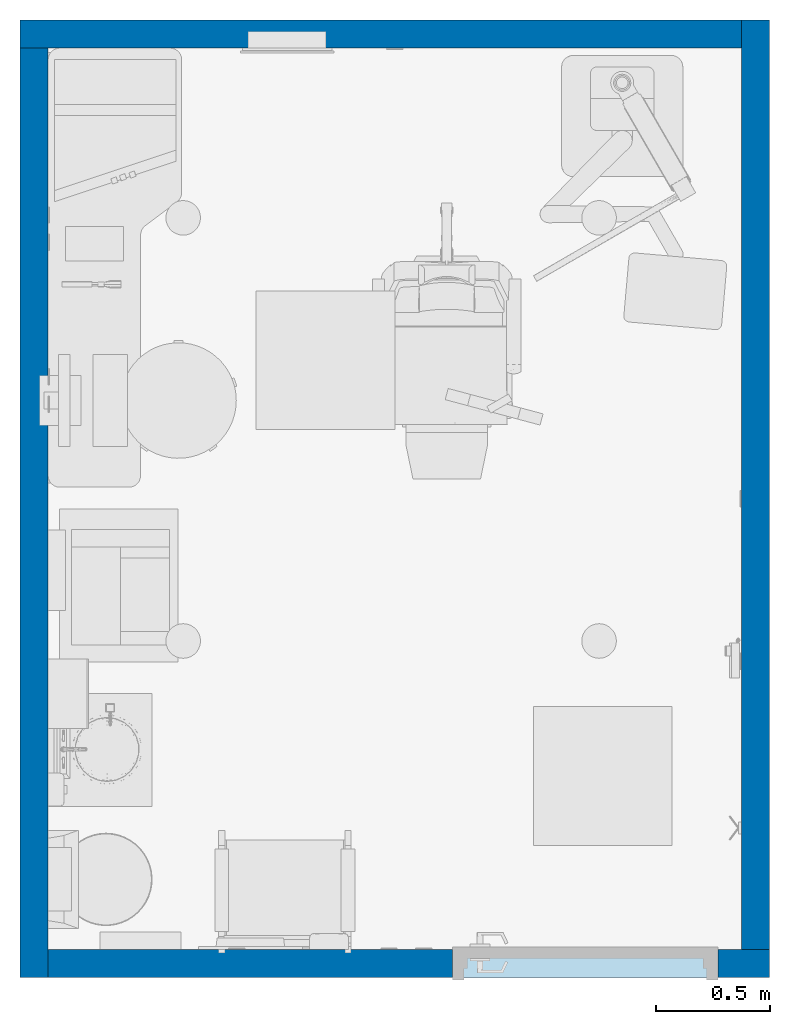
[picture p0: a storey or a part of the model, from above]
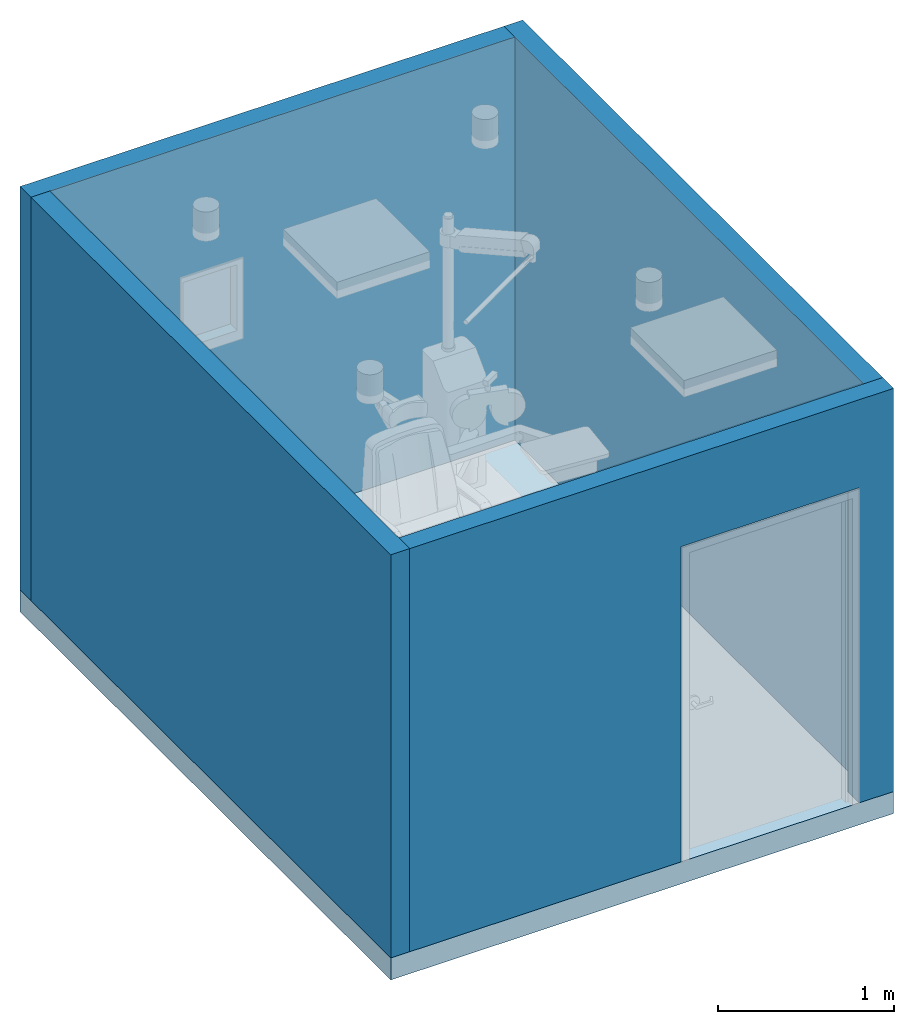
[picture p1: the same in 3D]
Properties of the parts of a building model (IFC2X3)

# File
Description: ViewDefinition [CoordinationView_V2.0]
File name: (ROOM CODE)
Time: 2018-06-28T12:58:41
Written by: The EXPRESS Data Manager Version 5.02.0100.07 : 28 Aug 2013
Made in: 20170223_1515(x64) - Exporter 18.0.0.420 - Alternate UI 18.0.0.420
Comment: STEP Physical File produced by: The EXPRESS Data Manager Version 5.02.0100.07 : 28 Aug 2013 * Module: EDMstepFileFactory/EDMstandAlone * Creation date: Thu Jun 28 12:58:41 2018 * Host: L105-OKC * Database: C:\Users\jet\AppData\Local\Temp\{96687613-B5EB-4AF7-9092-9E9E580CAC5A}\ifc * Database version: 5507 * Database creation date: Thu Jun 28 12:58:39 2018 * Schema: IFC2X3 * Model: DataRepository.ifc * Model creation date: Thu Jun 28 12:58:39 2018 * Header model: DataRepository.ifc_HeaderModel * Header model creation date: Thu Jun 28 12:58:39 2018 * EDMuser: sdai-user * EDMgroup: sdai-group * License ID and type: 5605 : Permanent license. Expiry date: * EDMstepFileFactory options: 020000

# IfcProject, (ROOM CODE)
LongName: ROOM NAME & AREA; Phase: DRAFT

# IfcSite, Default
RefLatitude: 42, 21, 31, 181945; RefLongitude: -71, -3, -24, -263305; RefElevation: 0 ft

# IfcBuilding, EYE CLINIC: OPTHALMOLOGY AND OPTOMETRY SERVICES (Ch. 233)
LongName: EYE CLINIC: OPTHALMOLOGY AND OPTOMETRY SERVICES (Ch. 233)
Pset_BuildingCommon - NumberOfStoreys: 1

# IfcBuildingStorey, DATUM
In: EYE CLINIC: OPTHALMOLOGY AND OPTOMETRY SERVICES (Ch. 233)
LongName: DATUM; Elevation: 0 ft

# IfcSpace, (OPET2)
In: DATUM
LongName: EXAM TREATMENT ROOM; InteriorOrExteriorSpace: INTERNAL
Pset_SpaceCommon - Reference: EXAM TREATMENT ROOM (OPET2); Category: Rooms; CeilingCovering: AT1; WallCovering: GPT; FloorCovering: UT

# IfcBuildingElementProxy: 24" x 24", Supply Diffuser:24" x 24":1366425
In: (OPET2)
Type - Classification: D3040100 Air Distribution Systems (Uniformat)
Pset_BuildingElementProxyCommon - Reference: 24" x 24"

# IfcBuildingElementProxy: 24" x 24", Return Register:24" x 24":1366590
In: (OPET2)
Type - Classification: D3040200 Exhaust Ventilation Systems (Uniformat)
Pset_BuildingElementProxyCommon - Reference: 24" x 24"

# IfcBuildingElementProxy: A1014 - Telephone, Wall Mounted, 1 Line, With Speaker 12"x 12", A1017 - Telephone, Wall Mounted, Multi-Line, With Speaker:A1014 - Telephone, Wall Mounted, 1 Line, With Speaker 12"x 12":2090981
In: (OPET2)
Type - Classification: VV (Uniformat)
Pset_BuildingElementProxyCommon - Reference: A1014 - Telephone, Wall Mounted, 1 Line, With Speaker 12"x 12"

# IfcBuildingElementProxy: A1066 - Mirror, Float Glass, A1066 - Mirror, Float Glass:A1066 - Mirror, Float Glass:1791967
In: (OPET2)
Type - Classification: CC (Uniformat); Material: mirror glass, Stainless Steel
Pset_BuildingElementProxyCommon - Reference: A1066 - Mirror, Float Glass

# IfcBuildingElementProxy: A5048 - Cabinet, Medication, Security, Wall Mounted, A5048 - Cabinet, Medication, Security, Wall Mounted:A5048 - Cabinet, Medication, Security, Wall Mounted:2480455
In: (OPET2)
Type - Classification: VV (Uniformat)
Pset_BuildingElementProxyCommon - Reference: A5048 - Cabinet, Medication, Security, Wall Mounted

# IfcBuildingElementProxy: A5075 - Dispenser, Soap, A5075 - Dispenser, Soap:A5075 - Dispenser, Soap:2013908
In: (OPET2)
Type - Classification: VV (Uniformat)
Pset_BuildingElementProxyCommon - Reference: A5075 - Dispenser, Soap

# IfcBuildingElementProxy: A5077 - Dispenser, Hand Sanitizer, Hands free, A5077 - Dispenser, Hand Sanitizer, Hands free:A5077 - Dispenser, Hand Sanitizer, Hands free:1366311
In: (OPET2)
Type - Classification: VV (Uniformat); Material: White Paint, Glass
Pset_BuildingElementProxyCommon - Reference: A5077 - Dispenser, Hand Sanitizer, Hands free

# IfcBuildingElementProxy: A5082 - Dispenser, Paper Towel, Sensor, Hands Free, A5082 - Dispenser, Paper Towel, Sensor, Hands Free:A5082 - Dispenser, Paper Towel, Sensor, Hands Free:1792067
In: (OPET2)
Type - Classification: CC (Uniformat)
Pset_BuildingElementProxyCommon - Reference: A5082 - Dispenser, Paper Towel, Sensor, Hands Free

# IfcBuildingElementProxy: A5107 - Dispenser, Glove, Surgical-Examination, Wall Mntd, A5107 - Dispenser, Glove, Surgical-Examination, Wall Mntd:A5107 - Dispenser, Glove, Surgical-Examination, Wall Mntd:2090615
In: (OPET2)
Type - Classification: VV (Uniformat)
Pset_BuildingElementProxyCommon - Reference: A5107 - Dispenser, Glove, Surgical-Examination, Wall Mntd

# IfcBuildingElementProxy: A5108 - Waste Disposal Unit, Sharps, A5108 - Waste Disposal Unit, Sharps:A5108 - Waste Disposal Unit, Sharps:1370386
In: DATUM
Type - Classification: VV (Uniformat)
Pset_BuildingElementProxyCommon - Reference: A5108 - Waste Disposal Unit, Sharps

# IfcBuildingElementProxy: A5145 - Hook, Garment, Double, A5145 - Hook, Garment, Double:A5145 - Hook, Garment, Double:1792139
In: (OPET2)
Type - Classification: CC (Uniformat)
Pset_BuildingElementProxyCommon - Reference: A5145 - Hook, Garment, Double

# IfcBuildingElementProxy: Duplex (5)
In: (OPET2)
Pset_BuildingElementProxyCommon - Reference: Duplex
Name (Outlet, Duplex, Wall:Duplex:...)
2381155
2381183
2381211
2381234
2381265

# IfcBuildingElementProxy: F0205 - Side Chair with Arms, F0205 - Side Chair with Arms:F0205 - Side Chair with Arms:1369252
In: (OPET2)
Type - Classification: VV (Uniformat)
Pset_BuildingElementProxyCommon - Reference: F0205 - Side Chair with Arms

# IfcBuildingElementProxy: F0340 - Stool, Self Adjusting, F0340 - Stool, Self Adjusting:F0340 - Stool, Self Adjusting:1792439
In: (OPET2)
Type - Classification: VV (Uniformat); Material: Stool caster, Stool metal, Stool cushion
Pset_BuildingElementProxyCommon - Reference: F0340 - Stool, Self Adjusting

# IfcBuildingElementProxy: F2000 - Basket, Wastepaper 16"x 16", F2000 - Basket, Wastepaper, Fire Resistant:F2000 - Basket, Wastepaper 16"x 16":2090845
In: (OPET2)
Type - Classification: VV (Uniformat)
Pset_BuildingElementProxyCommon - Reference: F2000 - Basket, Wastepaper 16"x 16"

# IfcBuildingElementProxy: F3200 - Clock, Battery, 12in Dia, F3200 - Clock, Battery, 12in Dia:F3200 - Clock, Battery, 12in Dia:1366273
In: (OPET2)
Type - Classification: VV (Uniformat); Material: WHITE
Pset_BuildingElementProxyCommon - Reference: F3200 - Clock, Battery, 12in Dia

# IfcBuildingElementProxy: M1801 Computer, M1801 - Computer, Microprocessing, With Flat Panel Monitor:M1801 Computer:1366271
In: (OPET2)
Type - Classification: VV (Uniformat)
Pset_BuildingElementProxyCommon - Reference: M1801 Computer

# IfcBuildingElementProxy: M1825 - Printer, Computer, M1825 - Printer, Computer:M1825 - Printer, Computer:1792551
In: (OPET2)
Type - Classification: VV (Uniformat)
Pset_BuildingElementProxyCommon - Reference: M1825 - Printer, Computer

# IfcBuildingElementProxy: M5015 - Desk, Refraction, with Sink, M5015 - Desk, Refraction, with Sink:M5015 - Desk, Refraction, with Sink:2010398
In: (OPET2)
Type - Classification: VC (Uniformat)
Pset_BuildingElementProxyCommon - Reference: M5015 - Desk, Refraction, with Sink

# IfcBuildingElementProxy: M5016 - Desk, Refraction w-console, w-o Sink, M5016 - Desk, Refraction w-console, w-o Sink:M5016 - Desk, Refraction w-console, w-o Sink:2481575
In: (OPET2)
Type - Material: Paint White
Pset_BuildingElementProxyCommon - Reference: M5016 - Desk, Refraction w-console, w-o Sink

# IfcBuildingElementProxy: M5562 - Tester, Visual Acuity, Video-Microprocessor Based (2)
In: (OPET2)
Type - Classification: VV (Uniformat)
Pset_BuildingElementProxyCommon - Reference: M5562 - Tester, Visual Acuity, Video-Microprocessor Based
Name (M5562 - Tester, Visual Acuity, Video-Microprocessor Based:M5562 - Tester, Visual Acuity, Video-Microprocessor Based:...)
1366330
2304009

# IfcBuildingElementProxy: M5599 - Phoropter, M5599 - Phoropter:M5599 - Phoropter:2179548
In: (OPET2)
Classification: VV (Uniformat)
Pset_BuildingElementProxyCommon - Reference: M5599 - Phoropter

# IfcBuildingElementProxy: M5601 - Chair, Glide, Exam (UXXX1), M5601 - Chair, Glide, Exam:M5601 - Chair, Glide, Exam (UXXX1):2176818
In: (OPET2)
Pset_BuildingElementProxyCommon - Reference: M5601 - Chair, Glide, Exam (UXXX1)

# IfcBuildingElementProxy: M5605 - Retinscope, Streak, M5605 - Retinscope, Streak:M5605 - Retinscope, Streak:2011563
In: (OPET2)
Type - Classification: VV (Uniformat)
Pset_BuildingElementProxyCommon - Reference: M5605 - Retinscope, Streak

# IfcBuildingElementProxy: M5705 - Gauge, Distance, Pupillary, M5705 - Gauge, Distance, Pupillary:M5705 - Gauge, Distance, Pupillary:1793346
In: (OPET2)
Type - Material: EquipSpace
Pset_BuildingElementProxyCommon - Reference: M5705 - Gauge, Distance, Pupillary

# IfcBuildingElementProxy: M5730 - Stand, Instrument, Ophthalmic, M5730 - Stand, Instrument, Ophthalmic:M5730 - Stand, Instrument, Ophthalmic:2206210
In: (OPET2)
Pset_BuildingElementProxyCommon - Reference: M5730 - Stand, Instrument, Ophthalmic

# IfcBuildingElementProxy: Single (2)
In: (OPET2)
Pset_BuildingElementProxyCommon - Reference: Single
Name (Switch, Single:Single:...)
2381428
2381465

# IfcBuildingElementProxy: Telephone/Data (3)
In: (OPET2)
Pset_BuildingElementProxyCommon - Reference: Telephone/Data
Name (Outlet, Communications:Telephone/Data:...)
2381300
2458974
2486817

# IfcBuildingElementProxy: UXX16 - Stand, Printer, Mobile, F0836 - Stand, Printer, Mobile:UXX16 - Stand, Printer, Mobile:2014907
In: DATUM
Type - Classification: VV (Uniformat)
Pset_BuildingElementProxyCommon - Reference: UXX16 - Stand, Printer, Mobile

# IfcCovering: Compound Ceiling:2' x 2' ACT System, Compound Ceiling:2' x 2' ACT System:1366405
In: (OPET2)
PredefinedType: CEILING; Classification: C3030210 Suspended Ceilings - Acoustical (Uniformat); Material: Default 0.135417 ft, Acoustic Ceiling Tile 24 x 24 0.0520833 ft
Pset_CoveringCommon - Reference: 2' x 2' ACT System; Finish: Acoustic Ceiling Tile 24 x 24;; TotalThickness: 0.1875 ft

# IfcDoor: 42" x 84", Single - Flush:42" x 84":2319592
In: DATUM
Type - ParameterTakesPrecedence: no; Sizeable: no; Classification: C1020 Interior Doors (Uniformat); Material: Door - Hardware, Door - Wood Panel, Door - H.M. Frame
OverallHeight: 7.16667 ft; OverallWidth: 3.83333 ft
Pset_DoorCommon - IsExternal: no; Reference: 42" x 84"

# IfcFlowTerminal: 6" (4)
In: (OPET2)
Type - Classification: D5020220 Lighting - Incandescent (Uniformat)
Pset_DistributionFlowElementCommon - Reference: 6"
Name (Downlight - Recessed Can:6":...)
1367246
1367438
2435001
2435002

# IfcOpeningElement: Recess, Basic Wall:Interior - 4 7/8":1971948
In: DATUM
Classification: B2010 Exterior Walls (Uniformat)

# IfcSlab: Floor:Generic - 6", Floor:Generic - 6":1369996
In: DATUM
PredefinedType: FLOOR; Classification: B1010 Floor Construction (Uniformat); Material: Default Floor 0.5 ft
Pset_SlabCommon - Reference: Generic - 6"; IsExternal: no; LoadBearing: no; PitchAngle: 0 deg

# IfcWallStandardCase: Basic Wall:Interior - 4 7/8" (4)
In: DATUM
Type - PredefinedType: STANDARD; Material: Default Wall 0.40625 ft
Classification: B2010 Exterior Walls (Uniformat)
Pset_WallCommon - LoadBearing: no; Reference: Interior - 4 7/8"; ExtendToStructure: no; IsExternal: yes
Name (Basic Wall:Interior - 4 7/8":...)
1971948
1972245
1973581
1974439
